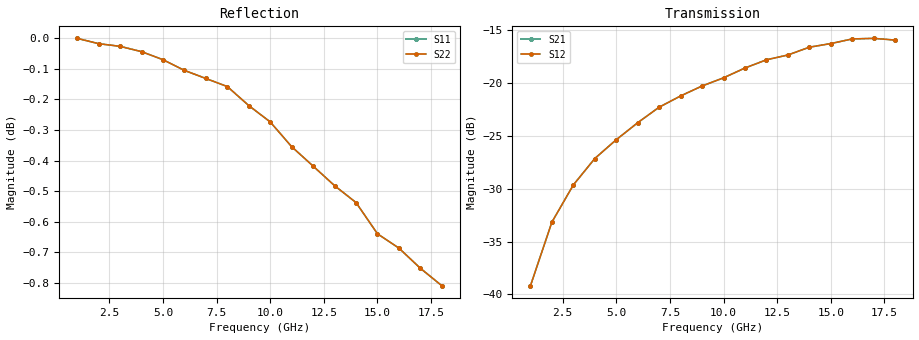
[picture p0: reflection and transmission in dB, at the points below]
!HPND-4018 beam lead PIN diode
!Series configuration S-parameters Vr=30 V.  Last updated 10/3/97
# mhz s ma r 50
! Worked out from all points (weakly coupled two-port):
!   18 points, 1 GHz to 18 GHz, reference 50 ohm
!   highest |S21| = -15.76 dB at 17 GHz (marker M1); lowest = -39.2 dB at 1 GHz (marker M2)
!   lowest |S11| = -0.8 dB at 18 GHz (marker M3), VSWR 21.47, Z = 23.9 - j150 ohm
!   |S11| at or under -10 dB: nowhere
!   |S22| runs from -0.8 to 0.0 dB; largest |S21 - S12| = 0
!   S11 on the Smith chart (normalised r, x): 1 GHz: -0, -57; 5 GHz: 1, -11; 12 GHz: 0.55, -4.64; 18 GHz: 0.48, -3.01
1000  1 -2.0  0.011 93.0  0.011 93.0  1 -2.0
2000  0.998 -4.0  0.022 87.0  0.022 87.0  0.998 -4.0
3000  0.997 -6.0  0.033 84.0  0.033 84.0  0.997 -6.0
4000  0.995 -8.0  0.044 82.0  0.044 82.0  0.995 -8.0
5000  0.992 -10.0  0.054 79.0  0.054 79.0  0.992 -10.0
6000  0.988 -12.0  0.065 77.0  0.065 77.0  0.988 -12.0
7000  0.985 -14.0  0.077 74.0  0.077 74.0  0.985 -14.0
8000  0.982 -16.0  0.087 72.0  0.087 72.0  0.982 -16.0
9000  0.975 -18.0  0.097 69.0  0.097 69.0  0.975 -18.0
10000  0.969 -20.0  0.106 68.0  0.106 68.0  0.969 -20.0
11000  0.96 -22.0  0.118 64.0  0.118 64.0  0.96 -22.0
12000  0.953 -24.0  0.129 63.0  0.129 63.0  0.953 -24.0
13000  0.946 -26.0  0.136 60.0  0.136 60.0  0.946 -26.0
14000  0.94 -29.0  0.148 56.0  0.148 56.0  0.94 -29.0
15000  0.929 -31.0  0.154 54.0  0.154 54.0  0.929 -31.0
16000  0.924 -32.0  0.162 49.0  0.162 49.0  0.924 -32.0
17000  0.917 -34.0  0.163 46.0  0.163 46.0  0.917 -34.0
18000  0.911 -36.0  0.16 42.0  0.16 42.0  0.911 -36.0
